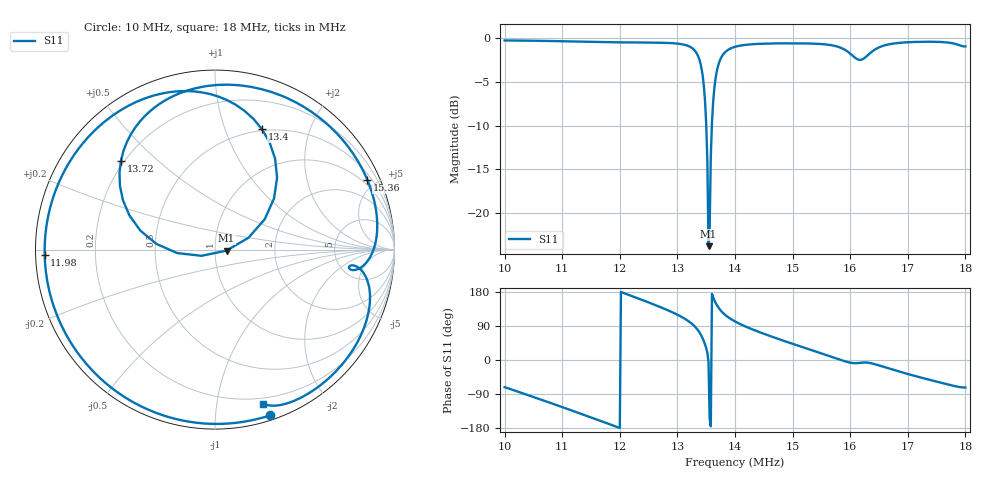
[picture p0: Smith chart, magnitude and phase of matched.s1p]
! NanoVNA Web complex sweep
! Processing: original sample grid, no browser smoothing
# Hz S RI R 50
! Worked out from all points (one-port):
!   401 points, 10 MHz to 18 MHz, reference 50 ohm
!   lowest |S11| = -23.8 dB at 13.54 MHz (marker M1), VSWR 1.14, Z = 56.9 - j0.639 ohm
!   |S11| at or under -10 dB: 13.5 MHz to 13.6 MHz (97.28 kHz wide, 0.718 % of centre)
!   S11 on the Smith chart (normalised r, x): 10 MHz: 0.04, -1.38; 11.98 MHz: 0.03, -0.02; 13.4 MHz: 0.49, +1.35; 13.72 MHz: 0.19, +0.38; 15.36 MHz: 0.75, +4.49; 18 MHz: 0.15, -1.35
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1e7  0.3067 -0.9237
1.05e7  -0.1277 -0.9614
1.1e7  -0.5415 -0.7961
1.152e7  -0.8477 -0.4389
1.198e7  -0.949 -0.0288
1.2e7  -0.9492 -0.01
1.252e7  -0.8257 0.4624
1.3e7  -0.4609 0.8123
1.326e7  -0.069 0.8753
1.34e7  0.2625 0.6698
1.348e7  0.3293 0.2863
1.352e7  0.1866 0.0661
1.354e7  0.0641 -0.0056
1.358e7  -0.21 -0.0195
1.364e7  -0.4764 0.1898
1.372e7  -0.5243 0.4942
1.384e7  -0.3904 0.7446
1.4e7  -0.1827 0.8763
1.444e7  0.2781 0.8887
1.5e7  0.6891 0.6361
1.536e7  0.8493 0.3873
1.572e7  0.9028 0.0967
1.6e7  0.8105 -0.1014
1.634e7  0.8123 -0.1115
1.662e7  0.8609 -0.3148
1.7e7  0.7592 -0.5723
1.758e7  0.4751 -0.8267
1.8e7  0.2671 -0.859
